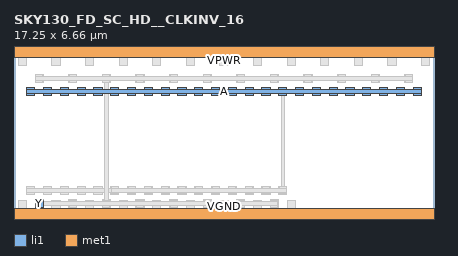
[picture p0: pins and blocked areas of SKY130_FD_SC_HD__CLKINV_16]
MACRO SKY130_FD_SC_HD__CLKINV_16
 CLASS CORE ;
 FOREIGN SKY130_FD_SC_HD__CLKINV_16 0 0 ;
 SIZE 17.25 BY 6.66 ;
 ORIGIN 0 0 ;
 SYMMETRY X Y R90 ;
 SITE unit ;
  PIN VPWR
   DIRECTION INOUT ;
   USE POWER ;
   SHAPE ABUTMENT ;
    PORT
     CLASS CORE ;
       LAYER li1 ;
        RECT 0.00000000 6.42000000 17.25000000 6.90000000 ;
       LAYER met1 ;
        RECT 0.00000000 6.42000000 17.25000000 6.90000000 ;
    END
  END VPWR

  PIN VGND
   DIRECTION INOUT ;
   USE POWER ;
   SHAPE ABUTMENT ;
    PORT
     CLASS CORE ;
       LAYER li1 ;
        RECT 0.00000000 -0.24000000 17.25000000 0.24000000 ;
       LAYER met1 ;
        RECT 0.00000000 -0.24000000 17.25000000 0.24000000 ;
    END
  END VGND

  PIN Y
   DIRECTION INOUT ;
   USE SIGNAL ;
   SHAPE ABUTMENT ;
    PORT
     CLASS CORE ;
       LAYER li1 ;
        RECT 0.87000000 0.26200000 1.20000000 0.59200000 ;
    END
  END Y

  PIN A
   DIRECTION INOUT ;
   USE SIGNAL ;
   SHAPE ABUTMENT ;
    PORT
     CLASS CORE ;
       LAYER li1 ;
        RECT 0.52500000 4.85200000 0.85500000 4.93200000 ;
        RECT 1.21500000 4.85200000 1.54500000 4.93200000 ;
        RECT 1.90500000 4.85200000 2.23500000 4.93200000 ;
        RECT 2.59500000 4.85200000 2.92500000 4.93200000 ;
        RECT 3.28500000 4.85200000 3.61500000 4.93200000 ;
        RECT 3.97500000 4.85200000 4.30500000 4.93200000 ;
        RECT 4.66500000 4.85200000 4.99500000 4.93200000 ;
        RECT 5.35500000 4.85200000 5.68500000 4.93200000 ;
        RECT 6.04500000 4.85200000 6.37500000 4.93200000 ;
        RECT 6.73500000 4.85200000 7.06500000 4.93200000 ;
        RECT 7.42500000 4.85200000 7.75500000 4.93200000 ;
        RECT 8.11500000 4.85200000 8.44500000 4.93200000 ;
        RECT 8.80500000 4.85200000 9.13500000 4.93200000 ;
        RECT 9.49500000 4.85200000 9.82500000 4.93200000 ;
        RECT 10.18500000 4.85200000 10.51500000 4.93200000 ;
        RECT 10.87500000 4.85200000 11.20500000 4.93200000 ;
        RECT 11.56500000 4.85200000 11.89500000 4.93200000 ;
        RECT 12.25500000 4.85200000 12.58500000 4.93200000 ;
        RECT 12.94500000 4.85200000 13.27500000 4.93200000 ;
        RECT 13.63500000 4.85200000 13.96500000 4.93200000 ;
        RECT 14.32500000 4.85200000 14.65500000 4.93200000 ;
        RECT 15.01500000 4.85200000 15.34500000 4.93200000 ;
        RECT 15.70500000 4.85200000 16.03500000 4.93200000 ;
        RECT 16.39500000 4.85200000 16.72500000 4.93200000 ;
        RECT 0.52500000 4.93200000 16.72500000 5.10200000 ;
        RECT 0.52500000 5.10200000 0.85500000 5.18200000 ;
        RECT 1.21500000 5.10200000 1.54500000 5.18200000 ;
        RECT 1.90500000 5.10200000 2.23500000 5.18200000 ;
        RECT 2.59500000 5.10200000 2.92500000 5.18200000 ;
        RECT 3.28500000 5.10200000 3.61500000 5.18200000 ;
        RECT 3.97500000 5.10200000 4.30500000 5.18200000 ;
        RECT 4.66500000 5.10200000 4.99500000 5.18200000 ;
        RECT 5.35500000 5.10200000 5.68500000 5.18200000 ;
        RECT 6.04500000 5.10200000 6.37500000 5.18200000 ;
        RECT 6.73500000 5.10200000 7.06500000 5.18200000 ;
        RECT 7.42500000 5.10200000 7.75500000 5.18200000 ;
        RECT 8.11500000 5.10200000 8.44500000 5.18200000 ;
        RECT 8.80500000 5.10200000 9.13500000 5.18200000 ;
        RECT 9.49500000 5.10200000 9.82500000 5.18200000 ;
        RECT 10.18500000 5.10200000 10.51500000 5.18200000 ;
        RECT 10.87500000 5.10200000 11.20500000 5.18200000 ;
        RECT 11.56500000 5.10200000 11.89500000 5.18200000 ;
        RECT 12.25500000 5.10200000 12.58500000 5.18200000 ;
        RECT 12.94500000 5.10200000 13.27500000 5.18200000 ;
        RECT 13.63500000 5.10200000 13.96500000 5.18200000 ;
        RECT 14.32500000 5.10200000 14.65500000 5.18200000 ;
        RECT 15.01500000 5.10200000 15.34500000 5.18200000 ;
        RECT 15.70500000 5.10200000 16.03500000 5.18200000 ;
        RECT 16.39500000 5.10200000 16.72500000 5.18200000 ;
    END
  END A

 OBS
    LAYER polycont ;
     RECT 0.60500000 0.88200000 0.77500000 1.05200000 ;
     RECT 1.29500000 0.88200000 1.46500000 1.05200000 ;
     RECT 1.98500000 0.88200000 2.15500000 1.05200000 ;
     RECT 2.67500000 0.88200000 2.84500000 1.05200000 ;
     RECT 3.36500000 0.88200000 3.53500000 1.05200000 ;
     RECT 4.05500000 0.88200000 4.22500000 1.05200000 ;
     RECT 4.74500000 0.88200000 4.91500000 1.05200000 ;
     RECT 5.43500000 0.88200000 5.60500000 1.05200000 ;
     RECT 6.12500000 0.88200000 6.29500000 1.05200000 ;
     RECT 6.81500000 0.88200000 6.98500000 1.05200000 ;
     RECT 7.50500000 0.88200000 7.67500000 1.05200000 ;
     RECT 8.19500000 0.88200000 8.36500000 1.05200000 ;
     RECT 8.88500000 0.88200000 9.05500000 1.05200000 ;
     RECT 9.57500000 0.88200000 9.74500000 1.05200000 ;
     RECT 10.26500000 0.88200000 10.43500000 1.05200000 ;
     RECT 10.95500000 0.88200000 11.12500000 1.05200000 ;
     RECT 0.60500000 4.93200000 0.77500000 5.10200000 ;
     RECT 1.29500000 4.93200000 1.46500000 5.10200000 ;
     RECT 1.98500000 4.93200000 2.15500000 5.10200000 ;
     RECT 2.67500000 4.93200000 2.84500000 5.10200000 ;
     RECT 3.36500000 4.93200000 3.53500000 5.10200000 ;
     RECT 4.05500000 4.93200000 4.22500000 5.10200000 ;
     RECT 4.74500000 4.93200000 4.91500000 5.10200000 ;
     RECT 5.43500000 4.93200000 5.60500000 5.10200000 ;
     RECT 6.12500000 4.93200000 6.29500000 5.10200000 ;
     RECT 6.81500000 4.93200000 6.98500000 5.10200000 ;
     RECT 7.50500000 4.93200000 7.67500000 5.10200000 ;
     RECT 8.19500000 4.93200000 8.36500000 5.10200000 ;
     RECT 8.88500000 4.93200000 9.05500000 5.10200000 ;
     RECT 9.57500000 4.93200000 9.74500000 5.10200000 ;
     RECT 10.26500000 4.93200000 10.43500000 5.10200000 ;
     RECT 10.95500000 4.93200000 11.12500000 5.10200000 ;
     RECT 11.64500000 4.93200000 11.81500000 5.10200000 ;
     RECT 12.33500000 4.93200000 12.50500000 5.10200000 ;
     RECT 13.02500000 4.93200000 13.19500000 5.10200000 ;
     RECT 13.71500000 4.93200000 13.88500000 5.10200000 ;
     RECT 14.40500000 4.93200000 14.57500000 5.10200000 ;
     RECT 15.09500000 4.93200000 15.26500000 5.10200000 ;
     RECT 15.78500000 4.93200000 15.95500000 5.10200000 ;
     RECT 16.47500000 4.93200000 16.64500000 5.10200000 ;

    LAYER pdiffc ;
     RECT 0.95000000 5.48000000 1.12000000 5.65000000 ;
     RECT 2.33000000 5.48000000 2.50000000 5.65000000 ;
     RECT 3.71000000 5.48000000 3.88000000 5.65000000 ;
     RECT 5.09000000 5.48000000 5.26000000 5.65000000 ;
     RECT 6.47000000 5.48000000 6.64000000 5.65000000 ;
     RECT 7.85000000 5.48000000 8.02000000 5.65000000 ;
     RECT 9.23000000 5.48000000 9.40000000 5.65000000 ;
     RECT 10.61000000 5.48000000 10.78000000 5.65000000 ;
     RECT 11.99000000 5.48000000 12.16000000 5.65000000 ;
     RECT 13.37000000 5.48000000 13.54000000 5.65000000 ;
     RECT 14.75000000 5.48000000 14.92000000 5.65000000 ;
     RECT 16.13000000 5.48000000 16.30000000 5.65000000 ;
     RECT 0.26000000 6.19000000 0.43000000 6.36000000 ;
     RECT 1.64000000 6.19000000 1.81000000 6.36000000 ;
     RECT 3.02000000 6.19000000 3.19000000 6.36000000 ;
     RECT 4.40000000 6.19000000 4.57000000 6.36000000 ;
     RECT 5.78000000 6.19000000 5.95000000 6.36000000 ;
     RECT 7.16000000 6.19000000 7.33000000 6.36000000 ;
     RECT 8.54000000 6.19000000 8.71000000 6.36000000 ;
     RECT 9.92000000 6.19000000 10.09000000 6.36000000 ;
     RECT 11.30000000 6.19000000 11.47000000 6.36000000 ;
     RECT 12.68000000 6.19000000 12.85000000 6.36000000 ;
     RECT 14.06000000 6.19000000 14.23000000 6.36000000 ;
     RECT 15.44000000 6.19000000 15.61000000 6.36000000 ;
     RECT 16.82000000 6.19000000 16.99000000 6.36000000 ;

    LAYER ndiffc ;
     RECT 0.95000000 0.34200000 1.12000000 0.51200000 ;
     RECT 2.33000000 0.34200000 2.50000000 0.51200000 ;
     RECT 3.71000000 0.34200000 3.88000000 0.51200000 ;
     RECT 5.09000000 0.34200000 5.26000000 0.51200000 ;
     RECT 6.47000000 0.34200000 6.64000000 0.51200000 ;
     RECT 7.85000000 0.34200000 8.02000000 0.51200000 ;
     RECT 9.23000000 0.34200000 9.40000000 0.51200000 ;
     RECT 10.61000000 0.34200000 10.78000000 0.51200000 ;
     RECT 0.26000000 0.30000000 0.43000000 0.47000000 ;
     RECT 1.64000000 0.30000000 1.81000000 0.47000000 ;
     RECT 3.02000000 0.30000000 3.19000000 0.47000000 ;
     RECT 4.40000000 0.30000000 4.57000000 0.47000000 ;
     RECT 5.78000000 0.30000000 5.95000000 0.47000000 ;
     RECT 7.16000000 0.30000000 7.33000000 0.47000000 ;
     RECT 8.54000000 0.30000000 8.71000000 0.47000000 ;
     RECT 9.92000000 0.30000000 10.09000000 0.47000000 ;
     RECT 11.30000000 0.30000000 11.47000000 0.47000000 ;

    LAYER li1 ;
     RECT 8.46000000 6.11000000 8.79000000 6.42000000 ;
     RECT 0.00000000 6.42000000 17.25000000 6.90000000 ;
     RECT 0.00000000 -0.24000000 17.25000000 0.24000000 ;
     RECT 8.46000000 0.24000000 8.79000000 0.55000000 ;
     RECT 0.52500000 4.93200000 16.72500000 5.10200000 ;
     RECT 16.05000000 5.40000000 16.38000000 5.73000000 ;
     RECT 9.15000000 5.40000000 9.48000000 5.73000000 ;
     RECT 9.84000000 6.11000000 10.17000000 6.42000000 ;
     RECT 11.22000000 6.11000000 11.55000000 6.42000000 ;
     RECT 12.60000000 6.11000000 12.93000000 6.42000000 ;
     RECT 13.98000000 6.11000000 14.31000000 6.42000000 ;
     RECT 15.36000000 6.11000000 15.69000000 6.42000000 ;
     RECT 16.74000000 6.11000000 17.07000000 6.42000000 ;
     RECT 10.53000000 5.40000000 10.86000000 5.73000000 ;
     RECT 11.91000000 5.40000000 12.24000000 5.73000000 ;
     RECT 13.29000000 5.40000000 13.62000000 5.73000000 ;
     RECT 8.80500000 4.85200000 9.13500000 4.93200000 ;
     RECT 9.49500000 4.85200000 9.82500000 4.93200000 ;
     RECT 10.18500000 4.85200000 10.51500000 4.93200000 ;
     RECT 10.87500000 4.85200000 11.20500000 4.93200000 ;
     RECT 11.56500000 4.85200000 11.89500000 4.93200000 ;
     RECT 12.25500000 4.85200000 12.58500000 4.93200000 ;
     RECT 12.94500000 4.85200000 13.27500000 4.93200000 ;
     RECT 13.63500000 4.85200000 13.96500000 4.93200000 ;
     RECT 14.32500000 4.85200000 14.65500000 4.93200000 ;
     RECT 15.01500000 4.85200000 15.34500000 4.93200000 ;
     RECT 15.70500000 4.85200000 16.03500000 4.93200000 ;
     RECT 16.39500000 4.85200000 16.72500000 4.93200000 ;
     RECT 14.67000000 5.40000000 15.00000000 5.73000000 ;
     RECT 8.80500000 5.10200000 9.13500000 5.18200000 ;
     RECT 9.49500000 5.10200000 9.82500000 5.18200000 ;
     RECT 10.18500000 5.10200000 10.51500000 5.18200000 ;
     RECT 10.87500000 5.10200000 11.20500000 5.18200000 ;
     RECT 11.56500000 5.10200000 11.89500000 5.18200000 ;
     RECT 12.25500000 5.10200000 12.58500000 5.18200000 ;
     RECT 12.94500000 5.10200000 13.27500000 5.18200000 ;
     RECT 13.63500000 5.10200000 13.96500000 5.18200000 ;
     RECT 14.32500000 5.10200000 14.65500000 5.18200000 ;
     RECT 15.01500000 5.10200000 15.34500000 5.18200000 ;
     RECT 15.70500000 5.10200000 16.03500000 5.18200000 ;
     RECT 16.39500000 5.10200000 16.72500000 5.18200000 ;
     RECT 7.08000000 6.11000000 7.41000000 6.42000000 ;
     RECT 0.87000000 5.40000000 1.20000000 5.73000000 ;
     RECT 2.25000000 5.40000000 2.58000000 5.73000000 ;
     RECT 3.63000000 5.40000000 3.96000000 5.73000000 ;
     RECT 5.01000000 5.40000000 5.34000000 5.73000000 ;
     RECT 6.39000000 5.40000000 6.72000000 5.73000000 ;
     RECT 7.77000000 5.40000000 8.10000000 5.73000000 ;
     RECT 0.18000000 6.11000000 0.51000000 6.42000000 ;
     RECT 1.56000000 6.11000000 1.89000000 6.42000000 ;
     RECT 2.94000000 6.11000000 3.27000000 6.42000000 ;
     RECT 4.32000000 6.11000000 4.65000000 6.42000000 ;
     RECT 0.52500000 4.85200000 0.85500000 4.93200000 ;
     RECT 0.52500000 5.10200000 0.85500000 5.18200000 ;
     RECT 1.21500000 5.10200000 1.54500000 5.18200000 ;
     RECT 1.90500000 5.10200000 2.23500000 5.18200000 ;
     RECT 2.59500000 5.10200000 2.92500000 5.18200000 ;
     RECT 3.28500000 5.10200000 3.61500000 5.18200000 ;
     RECT 3.97500000 5.10200000 4.30500000 5.18200000 ;
     RECT 4.66500000 5.10200000 4.99500000 5.18200000 ;
     RECT 5.35500000 5.10200000 5.68500000 5.18200000 ;
     RECT 6.04500000 5.10200000 6.37500000 5.18200000 ;
     RECT 6.73500000 5.10200000 7.06500000 5.18200000 ;
     RECT 7.42500000 5.10200000 7.75500000 5.18200000 ;
     RECT 8.11500000 5.10200000 8.44500000 5.18200000 ;
     RECT 1.21500000 4.85200000 1.54500000 4.93200000 ;
     RECT 1.90500000 4.85200000 2.23500000 4.93200000 ;
     RECT 2.59500000 4.85200000 2.92500000 4.93200000 ;
     RECT 3.28500000 4.85200000 3.61500000 4.93200000 ;
     RECT 3.97500000 4.85200000 4.30500000 4.93200000 ;
     RECT 4.66500000 4.85200000 4.99500000 4.93200000 ;
     RECT 5.35500000 4.85200000 5.68500000 4.93200000 ;
     RECT 6.04500000 4.85200000 6.37500000 4.93200000 ;
     RECT 6.73500000 4.85200000 7.06500000 4.93200000 ;
     RECT 7.42500000 4.85200000 7.75500000 4.93200000 ;
     RECT 8.11500000 4.85200000 8.44500000 4.93200000 ;
     RECT 5.70000000 6.11000000 6.03000000 6.42000000 ;
     RECT 0.52500000 0.88200000 4.30500000 1.05200000 ;
     RECT 0.52500000 1.05200000 0.85500000 1.13200000 ;
     RECT 1.21500000 1.05200000 1.54500000 1.13200000 ;
     RECT 1.90500000 1.05200000 2.23500000 1.13200000 ;
     RECT 2.59500000 1.05200000 2.92500000 1.13200000 ;
     RECT 3.28500000 1.05200000 3.61500000 1.13200000 ;
     RECT 3.97500000 1.05200000 4.30500000 1.13200000 ;
     RECT 4.66500000 0.80200000 4.99500000 1.13200000 ;
     RECT 5.35500000 0.80200000 5.68500000 1.13200000 ;
     RECT 6.04500000 0.80200000 6.37500000 1.13200000 ;
     RECT 6.73500000 0.80200000 7.06500000 1.13200000 ;
     RECT 7.42500000 0.80200000 7.75500000 1.13200000 ;
     RECT 8.11500000 0.80200000 8.44500000 1.13200000 ;
     RECT 6.39000000 0.26200000 6.72000000 0.59200000 ;
     RECT 7.77000000 0.26200000 8.10000000 0.59200000 ;
     RECT 0.87000000 0.26200000 1.20000000 0.59200000 ;
     RECT 2.25000000 0.26200000 2.58000000 0.59200000 ;
     RECT 3.63000000 0.26200000 3.96000000 0.59200000 ;
     RECT 0.18000000 0.24000000 0.51000000 0.55000000 ;
     RECT 1.56000000 0.24000000 1.89000000 0.55000000 ;
     RECT 2.94000000 0.24000000 3.27000000 0.55000000 ;
     RECT 4.32000000 0.24000000 4.65000000 0.55000000 ;
     RECT 5.70000000 0.24000000 6.03000000 0.55000000 ;
     RECT 7.08000000 0.24000000 7.41000000 0.55000000 ;
     RECT 5.01000000 0.26200000 5.34000000 0.59200000 ;
     RECT 0.52500000 0.80200000 0.85500000 0.88200000 ;
     RECT 1.21500000 0.80200000 1.54500000 0.88200000 ;
     RECT 1.90500000 0.80200000 2.23500000 0.88200000 ;
     RECT 2.59500000 0.80200000 2.92500000 0.88200000 ;
     RECT 3.28500000 0.80200000 3.61500000 0.88200000 ;
     RECT 3.97500000 0.80200000 4.30500000 0.88200000 ;
     RECT 9.15000000 0.26200000 9.48000000 0.59200000 ;
     RECT 10.53000000 0.26200000 10.86000000 0.59200000 ;
     RECT 9.84000000 0.24000000 10.17000000 0.55000000 ;
     RECT 8.80500000 0.80200000 9.13500000 1.13200000 ;
     RECT 9.49500000 0.80200000 9.82500000 1.13200000 ;
     RECT 10.18500000 0.80200000 10.51500000 1.13200000 ;
     RECT 10.87500000 0.80200000 11.20500000 1.13200000 ;
     RECT 11.22000000 0.24000000 11.55000000 0.55000000 ;

    LAYER viali ;
     RECT 0.95000000 0.34200000 1.12000000 0.51200000 ;
     RECT 2.33000000 0.34200000 2.50000000 0.51200000 ;
     RECT 3.71000000 0.34200000 3.88000000 0.51200000 ;
     RECT 5.09000000 0.34200000 5.26000000 0.51200000 ;
     RECT 6.47000000 0.34200000 6.64000000 0.51200000 ;
     RECT 7.85000000 0.34200000 8.02000000 0.51200000 ;
     RECT 9.23000000 0.34200000 9.40000000 0.51200000 ;
     RECT 10.61000000 0.34200000 10.78000000 0.51200000 ;
     RECT 0.95000000 5.48000000 1.12000000 5.65000000 ;
     RECT 2.33000000 5.48000000 2.50000000 5.65000000 ;
     RECT 3.71000000 5.48000000 3.88000000 5.65000000 ;
     RECT 5.09000000 5.48000000 5.26000000 5.65000000 ;
     RECT 6.47000000 5.48000000 6.64000000 5.65000000 ;
     RECT 7.85000000 5.48000000 8.02000000 5.65000000 ;
     RECT 9.23000000 5.48000000 9.40000000 5.65000000 ;
     RECT 10.61000000 5.48000000 10.78000000 5.65000000 ;
     RECT 11.99000000 5.48000000 12.16000000 5.65000000 ;
     RECT 13.37000000 5.48000000 13.54000000 5.65000000 ;
     RECT 14.75000000 5.48000000 14.92000000 5.65000000 ;
     RECT 16.13000000 5.48000000 16.30000000 5.65000000 ;
     RECT 5.78000000 6.57500000 5.95000000 6.74500000 ;
     RECT 3.02000000 -0.08500000 3.19000000 0.08500000 ;
     RECT 4.05500000 0.88200000 4.22500000 1.05200000 ;
     RECT 4.74500000 0.88200000 4.91500000 1.05200000 ;
     RECT 5.43500000 0.88200000 5.60500000 1.05200000 ;
     RECT 6.12500000 0.88200000 6.29500000 1.05200000 ;
     RECT 6.81500000 0.88200000 6.98500000 1.05200000 ;
     RECT 7.50500000 0.88200000 7.67500000 1.05200000 ;
     RECT 8.19500000 0.88200000 8.36500000 1.05200000 ;
     RECT 8.88500000 0.88200000 9.05500000 1.05200000 ;
     RECT 9.57500000 0.88200000 9.74500000 1.05200000 ;
     RECT 10.26500000 0.88200000 10.43500000 1.05200000 ;
     RECT 10.95500000 0.88200000 11.12500000 1.05200000 ;
     RECT 10.95500000 4.93200000 11.12500000 5.10200000 ;

    LAYER met1 ;
     RECT 0.89000000 0.28200000 1.18000000 0.35700000 ;
     RECT 2.27000000 0.28200000 2.56000000 0.35700000 ;
     RECT 3.65000000 0.28200000 3.94000000 0.35700000 ;
     RECT 5.03000000 0.28200000 5.32000000 0.35700000 ;
     RECT 6.41000000 0.28200000 6.70000000 0.35700000 ;
     RECT 7.79000000 0.28200000 8.08000000 0.35700000 ;
     RECT 9.17000000 0.28200000 9.46000000 0.35700000 ;
     RECT 10.55000000 0.28200000 10.84000000 0.35700000 ;
     RECT 0.89000000 0.35700000 10.84000000 0.49700000 ;
     RECT 0.89000000 0.49700000 1.18000000 0.57200000 ;
     RECT 2.27000000 0.49700000 2.56000000 0.57200000 ;
     RECT 3.65000000 0.49700000 3.94000000 0.57200000 ;
     RECT 5.03000000 0.49700000 5.32000000 0.57200000 ;
     RECT 6.41000000 0.49700000 6.70000000 0.57200000 ;
     RECT 7.79000000 0.49700000 8.08000000 0.57200000 ;
     RECT 9.17000000 0.49700000 9.46000000 0.57200000 ;
     RECT 10.55000000 0.49700000 10.84000000 0.57200000 ;
     RECT 3.72500000 0.57200000 3.86500000 5.42000000 ;
     RECT 0.89000000 5.42000000 1.18000000 5.49500000 ;
     RECT 2.27000000 5.42000000 2.56000000 5.49500000 ;
     RECT 3.65000000 5.42000000 3.94000000 5.49500000 ;
     RECT 5.03000000 5.42000000 5.32000000 5.49500000 ;
     RECT 6.41000000 5.42000000 6.70000000 5.49500000 ;
     RECT 7.79000000 5.42000000 8.08000000 5.49500000 ;
     RECT 9.17000000 5.42000000 9.46000000 5.49500000 ;
     RECT 10.55000000 5.42000000 10.84000000 5.49500000 ;
     RECT 11.93000000 5.42000000 12.22000000 5.49500000 ;
     RECT 13.31000000 5.42000000 13.60000000 5.49500000 ;
     RECT 14.69000000 5.42000000 14.98000000 5.49500000 ;
     RECT 16.07000000 5.42000000 16.36000000 5.49500000 ;
     RECT 0.89000000 5.49500000 16.36000000 5.63500000 ;
     RECT 0.89000000 5.63500000 1.18000000 5.71000000 ;
     RECT 2.27000000 5.63500000 2.56000000 5.71000000 ;
     RECT 3.65000000 5.63500000 3.94000000 5.71000000 ;
     RECT 5.03000000 5.63500000 5.32000000 5.71000000 ;
     RECT 6.41000000 5.63500000 6.70000000 5.71000000 ;
     RECT 7.79000000 5.63500000 8.08000000 5.71000000 ;
     RECT 9.17000000 5.63500000 9.46000000 5.71000000 ;
     RECT 10.55000000 5.63500000 10.84000000 5.71000000 ;
     RECT 11.93000000 5.63500000 12.22000000 5.71000000 ;
     RECT 13.31000000 5.63500000 13.60000000 5.71000000 ;
     RECT 14.69000000 5.63500000 14.98000000 5.71000000 ;
     RECT 16.07000000 5.63500000 16.36000000 5.71000000 ;
     RECT 0.00000000 6.42000000 17.25000000 6.90000000 ;
     RECT 0.00000000 -0.24000000 17.25000000 0.24000000 ;
     RECT 3.99500000 0.82200000 4.28500000 0.89700000 ;
     RECT 4.68500000 0.82200000 4.97500000 0.89700000 ;
     RECT 5.37500000 0.82200000 5.66500000 0.89700000 ;
     RECT 6.06500000 0.82200000 6.35500000 0.89700000 ;
     RECT 6.75500000 0.82200000 7.04500000 0.89700000 ;
     RECT 7.44500000 0.82200000 7.73500000 0.89700000 ;
     RECT 8.13500000 0.82200000 8.42500000 0.89700000 ;
     RECT 8.82500000 0.82200000 9.11500000 0.89700000 ;
     RECT 9.51500000 0.82200000 9.80500000 0.89700000 ;
     RECT 10.20500000 0.82200000 10.49500000 0.89700000 ;
     RECT 10.89500000 0.82200000 11.18500000 0.89700000 ;
     RECT 3.99500000 0.89700000 11.18500000 1.03700000 ;
     RECT 3.99500000 1.03700000 4.28500000 1.11200000 ;
     RECT 4.68500000 1.03700000 4.97500000 1.11200000 ;
     RECT 5.37500000 1.03700000 5.66500000 1.11200000 ;
     RECT 6.06500000 1.03700000 6.35500000 1.11200000 ;
     RECT 6.75500000 1.03700000 7.04500000 1.11200000 ;
     RECT 7.44500000 1.03700000 7.73500000 1.11200000 ;
     RECT 8.13500000 1.03700000 8.42500000 1.11200000 ;
     RECT 8.82500000 1.03700000 9.11500000 1.11200000 ;
     RECT 9.51500000 1.03700000 9.80500000 1.11200000 ;
     RECT 10.20500000 1.03700000 10.49500000 1.11200000 ;
     RECT 10.89500000 1.03700000 11.18500000 1.11200000 ;
     RECT 10.97000000 1.11200000 11.11000000 4.87200000 ;
     RECT 10.89500000 4.87200000 11.18500000 5.16200000 ;

    LAYER via ;


    LAYER met2 ;


    LAYER via2 ;


    LAYER met3 ;


 END
END SKY130_FD_SC_HD__CLKINV_16
